VERSION 5.7 ;
  NOWIREEXTENSIONATPIN ON ;
  DIVIDERCHAR "/" ;
  BUSBITCHARS "[]" ;
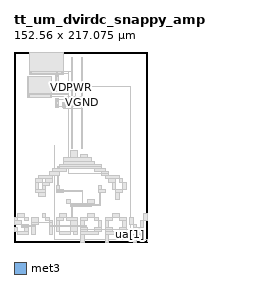
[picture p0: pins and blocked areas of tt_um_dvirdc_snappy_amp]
MACRO tt_um_dvirdc_snappy_amp
  CLASS BLOCK ;
  FOREIGN tt_um_dvirdc_snappy_amp ;
  ORIGIN 0.000 0.000 ;
  SIZE 152.560 BY 217.075 ;
  PIN VDPWR
    DIRECTION INOUT ;
    USE POWER ;
    PORT
      LAYER met3 ;
        RECT 65.995 175.995 66.005 176.005 ;
    END
  END VDPWR
  PIN VGND
    DIRECTION INOUT ;
    USE GROUND ;
    PORT
      LAYER met3 ;
        RECT 77.995 158.995 78.005 159.005 ;
    END
  END VGND
  PIN ua[0]
    DIRECTION INOUT ;
    USE ANALOG ;
    PORT
      LAYER met3 ;
        RECT 152.255 0.595 152.265 0.605 ;
    END
  END ua[0]
  PIN ua[1]
    DIRECTION INOUT ;
    USE ANALOG ;
    ANTENNADIFFAREA 2.320000 ;
    PORT
      LAYER met3 ;
        RECT 132.935 0.995 132.945 1.005 ;
    END
  END ua[1]
  OBS
      LAYER pwell ;
        RECT 17.735 191.735 56.715 217.075 ;
        RECT 15.735 164.735 43.375 189.075 ;
        RECT 47.735 171.735 50.805 191.655 ;
        RECT 47.735 153.735 50.805 163.955 ;
        RECT 55.735 153.735 58.985 159.835 ;
      LAYER li1 ;
        RECT 17.915 216.725 56.535 216.895 ;
        RECT 17.915 192.085 18.085 216.725 ;
        RECT 18.565 192.565 19.975 194.725 ;
        RECT 54.475 192.565 55.885 194.725 ;
        RECT 19.050 192.520 19.490 192.565 ;
        RECT 54.960 192.520 55.400 192.565 ;
        RECT 56.365 192.085 56.535 216.725 ;
        RECT 17.915 191.915 56.535 192.085 ;
        RECT 47.915 191.305 50.625 191.475 ;
        RECT 15.915 188.725 43.195 188.895 ;
        RECT 15.915 165.085 16.085 188.725 ;
        RECT 16.565 165.565 17.975 167.725 ;
        RECT 41.135 165.565 42.545 167.725 ;
        RECT 17.050 165.520 17.490 165.565 ;
        RECT 41.620 165.520 42.060 165.565 ;
        RECT 43.025 165.085 43.195 188.725 ;
        RECT 47.915 172.085 48.085 191.305 ;
        RECT 49.050 190.825 49.490 190.870 ;
        RECT 48.565 188.665 49.975 190.825 ;
        RECT 48.565 172.565 49.975 174.725 ;
        RECT 49.050 172.520 49.490 172.565 ;
        RECT 50.455 172.085 50.625 191.305 ;
        RECT 47.915 171.915 50.625 172.085 ;
        RECT 15.915 164.915 43.195 165.085 ;
        RECT 47.915 163.605 50.625 163.775 ;
        RECT 47.915 154.085 48.085 163.605 ;
        RECT 49.050 163.125 49.490 163.170 ;
        RECT 48.565 160.965 49.975 163.125 ;
        RECT 48.565 154.565 49.975 156.725 ;
        RECT 49.050 154.520 49.490 154.565 ;
        RECT 50.455 154.085 50.625 163.605 ;
        RECT 47.915 153.915 50.625 154.085 ;
        RECT 55.915 159.485 58.805 159.655 ;
        RECT 55.915 154.085 56.085 159.485 ;
        RECT 56.715 158.975 57.215 159.145 ;
        RECT 57.505 158.975 58.005 159.145 ;
        RECT 56.485 154.765 56.655 158.805 ;
        RECT 57.275 154.765 57.445 158.805 ;
        RECT 58.065 154.765 58.235 158.805 ;
        RECT 56.715 154.425 57.215 154.595 ;
        RECT 57.505 154.425 58.005 154.595 ;
        RECT 58.635 154.085 58.805 159.485 ;
        RECT 55.915 153.915 58.805 154.085 ;
      LAYER met1 ;
        RECT 18.615 192.595 19.925 194.700 ;
        RECT 54.525 192.595 55.835 194.700 ;
        RECT 19.020 192.490 19.520 192.595 ;
        RECT 54.930 192.490 55.430 192.595 ;
        RECT 49.020 190.795 49.520 190.900 ;
        RECT 48.615 188.690 49.925 190.795 ;
        RECT 48.615 172.595 49.925 174.700 ;
        RECT 49.020 172.490 49.520 172.595 ;
        RECT 16.615 165.595 17.925 167.700 ;
        RECT 41.185 165.595 42.495 167.700 ;
        RECT 17.020 165.490 17.520 165.595 ;
        RECT 41.590 165.490 42.090 165.595 ;
        RECT 49.020 163.095 49.520 163.200 ;
        RECT 48.615 160.990 49.925 163.095 ;
        RECT 59.250 159.290 59.750 159.390 ;
        RECT 56.820 159.175 59.750 159.290 ;
        RECT 56.735 158.990 59.750 159.175 ;
        RECT 56.735 158.945 57.195 158.990 ;
        RECT 57.525 158.945 57.985 158.990 ;
        RECT 59.250 158.890 59.750 158.990 ;
        RECT 56.455 157.030 56.685 158.785 ;
        RECT 57.245 157.030 57.475 158.785 ;
        RECT 58.035 157.030 58.265 158.785 ;
        RECT 48.615 154.595 49.925 156.700 ;
        RECT 56.320 156.530 56.820 157.030 ;
        RECT 57.110 156.530 57.610 157.030 ;
        RECT 57.900 156.530 58.400 157.030 ;
        RECT 56.455 154.785 56.685 156.530 ;
        RECT 57.245 154.785 57.475 156.530 ;
        RECT 58.035 154.785 58.265 156.530 ;
        RECT 49.020 154.490 49.520 154.595 ;
        RECT 56.735 154.395 57.195 154.625 ;
        RECT 57.525 154.395 57.985 154.625 ;
        RECT 57.110 153.750 57.610 154.250 ;
      LAYER met2 ;
        RECT 65.850 195.280 66.150 195.650 ;
        RECT 65.720 194.720 66.280 195.280 ;
        RECT 61.850 193.020 62.150 193.150 ;
        RECT 18.990 192.460 19.550 193.020 ;
        RECT 54.900 192.460 55.460 193.020 ;
        RECT 61.720 192.460 62.280 193.020 ;
        RECT 48.990 190.370 49.550 190.930 ;
        RECT 48.990 172.460 49.550 173.020 ;
        RECT 61.850 169.280 62.150 192.460 ;
        RECT 65.850 189.850 66.150 194.720 ;
        RECT 69.850 177.850 133.090 178.150 ;
        RECT 65.720 175.720 66.280 176.280 ;
        RECT 69.850 173.020 70.150 177.850 ;
        RECT 69.720 172.460 70.280 173.020 ;
        RECT 61.720 168.720 62.280 169.280 ;
        RECT 16.990 165.460 17.550 166.020 ;
        RECT 41.560 165.460 42.120 166.020 ;
        RECT 48.990 162.670 49.550 163.230 ;
        RECT 61.850 159.420 62.150 168.720 ;
        RECT 59.220 158.860 59.780 159.420 ;
        RECT 61.720 158.860 62.280 159.420 ;
        RECT 56.290 158.150 56.850 158.280 ;
        RECT 56.290 157.850 58.300 158.150 ;
        RECT 56.290 157.720 56.850 157.850 ;
        RECT 56.420 157.030 56.720 157.720 ;
        RECT 58.000 157.030 58.300 157.850 ;
        RECT 56.320 156.530 56.820 157.030 ;
        RECT 57.110 156.530 57.610 157.030 ;
        RECT 57.900 156.530 58.400 157.030 ;
        RECT 57.210 155.780 57.510 156.530 ;
        RECT 57.080 155.220 57.640 155.780 ;
        RECT 48.990 154.460 49.550 155.020 ;
        RECT 57.110 153.750 57.610 154.250 ;
        RECT 57.210 153.080 57.510 153.750 ;
        RECT 57.080 152.520 57.640 153.080 ;
        RECT 61.850 108.280 62.150 158.860 ;
        RECT 69.850 158.280 70.150 172.460 ;
        RECT 77.720 166.220 78.280 166.780 ;
        RECT 73.850 163.230 74.150 163.650 ;
        RECT 73.720 162.670 74.280 163.230 ;
        RECT 69.720 157.720 70.280 158.280 ;
        RECT 69.850 154.850 70.150 157.720 ;
        RECT 73.850 155.780 74.150 162.670 ;
        RECT 77.850 159.280 78.150 166.220 ;
        RECT 77.720 158.720 78.280 159.280 ;
        RECT 73.720 155.220 74.280 155.780 ;
        RECT 73.850 154.850 74.150 155.220 ;
        RECT 77.850 155.020 78.150 158.720 ;
        RECT 77.720 154.460 78.280 155.020 ;
        RECT 77.850 153.080 78.150 154.460 ;
        RECT 77.720 152.520 78.280 153.080 ;
        RECT 77.850 152.350 78.150 152.520 ;
        RECT 61.720 107.720 62.280 108.280 ;
        RECT 61.850 77.850 62.150 107.720 ;
        RECT 132.790 1.280 133.090 177.850 ;
        RECT 132.660 0.720 133.220 1.280 ;
      LAYER met3 ;
        RECT 65.720 195.160 66.280 195.280 ;
        RECT 19.110 194.840 66.280 195.160 ;
        RECT 19.110 193.020 19.430 194.840 ;
        RECT 18.990 192.460 19.550 193.020 ;
        RECT 49.110 190.930 49.430 194.840 ;
        RECT 65.720 194.720 66.280 194.840 ;
        RECT 54.900 192.900 55.460 193.020 ;
        RECT 61.720 192.900 62.280 193.020 ;
        RECT 54.900 192.580 62.280 192.900 ;
        RECT 54.900 192.460 55.460 192.580 ;
        RECT 61.720 192.460 62.280 192.580 ;
        RECT 48.990 190.370 49.550 190.930 ;
        RECT 65.700 175.700 66.300 176.300 ;
        RECT 48.990 172.900 49.550 173.020 ;
        RECT 69.720 172.900 70.280 173.020 ;
        RECT 48.990 172.580 70.280 172.900 ;
        RECT 48.990 172.460 49.550 172.580 ;
        RECT 69.720 172.460 70.280 172.580 ;
        RECT 61.720 169.160 62.280 169.280 ;
        RECT 17.110 168.840 62.280 169.160 ;
        RECT 17.110 166.020 17.430 168.840 ;
        RECT 61.720 168.720 62.280 168.840 ;
        RECT 77.720 166.660 78.280 166.780 ;
        RECT 41.680 166.340 78.280 166.660 ;
        RECT 41.680 166.020 42.000 166.340 ;
        RECT 77.720 166.220 78.280 166.340 ;
        RECT 16.990 165.460 17.550 166.020 ;
        RECT 41.560 165.460 42.120 166.020 ;
        RECT 48.990 163.110 49.550 163.230 ;
        RECT 73.720 163.110 74.280 163.230 ;
        RECT 48.990 162.790 74.280 163.110 ;
        RECT 48.990 162.670 49.550 162.790 ;
        RECT 73.720 162.670 74.280 162.790 ;
        RECT 59.220 159.300 59.780 159.420 ;
        RECT 61.720 159.300 62.280 159.420 ;
        RECT 59.220 158.980 62.280 159.300 ;
        RECT 59.220 158.860 59.780 158.980 ;
        RECT 61.720 158.860 62.280 158.980 ;
        RECT 77.700 158.700 78.300 159.300 ;
        RECT 56.290 158.160 56.850 158.280 ;
        RECT 69.720 158.160 70.280 158.280 ;
        RECT 56.290 157.840 70.280 158.160 ;
        RECT 56.290 157.720 56.850 157.840 ;
        RECT 69.720 157.720 70.280 157.840 ;
        RECT 57.080 155.660 57.640 155.780 ;
        RECT 73.720 155.660 74.280 155.780 ;
        RECT 57.080 155.340 74.280 155.660 ;
        RECT 57.080 155.220 57.640 155.340 ;
        RECT 73.720 155.220 74.280 155.340 ;
        RECT 48.990 154.900 49.550 155.020 ;
        RECT 77.720 154.900 78.280 155.020 ;
        RECT 48.990 154.580 78.280 154.900 ;
        RECT 48.990 154.460 49.550 154.580 ;
        RECT 77.720 154.460 78.280 154.580 ;
        RECT 57.080 152.960 57.640 153.080 ;
        RECT 77.720 152.960 78.280 153.080 ;
        RECT 57.080 152.640 78.280 152.960 ;
        RECT 57.080 152.520 57.640 152.640 ;
        RECT 77.720 152.520 78.280 152.640 ;
        RECT 46.000 84.400 46.400 110.200 ;
        RECT 61.700 107.700 62.300 108.300 ;
        RECT 64.000 96.400 72.400 104.400 ;
        RECT 76.000 96.400 84.400 100.400 ;
        RECT 56.000 92.400 88.400 96.400 ;
        RECT 56.000 88.400 92.400 92.400 ;
        RECT 52.000 86.450 100.400 88.400 ;
        RECT 49.950 85.950 100.400 86.450 ;
        RECT 49.950 84.400 50.450 85.950 ;
        RECT 52.000 84.400 100.400 85.950 ;
        RECT 44.000 84.000 104.400 84.400 ;
        RECT 44.000 80.400 60.400 84.000 ;
        RECT 40.000 80.000 60.400 80.400 ;
        RECT 92.000 80.400 104.400 84.000 ;
        RECT 92.000 80.000 108.400 80.400 ;
        RECT 40.000 76.400 52.400 80.000 ;
        RECT 28.000 76.000 52.400 76.400 ;
        RECT 100.000 76.400 108.400 80.000 ;
        RECT 100.000 76.000 120.400 76.400 ;
        RECT 28.000 72.400 44.400 76.000 ;
        RECT 24.000 72.000 44.400 72.400 ;
        RECT 24.000 68.400 32.400 72.000 ;
        RECT 36.000 68.400 44.400 72.000 ;
        RECT 24.000 68.000 44.400 68.400 ;
        RECT 24.000 60.400 28.400 68.000 ;
        RECT 32.000 64.000 40.400 68.000 ;
        RECT 32.000 60.400 36.400 64.000 ;
        RECT 24.000 56.000 36.400 60.400 ;
        RECT 28.000 52.000 36.400 56.000 ;
        RECT 4.000 28.400 12.400 32.400 ;
        RECT 32.000 28.400 36.400 32.400 ;
        RECT 0.000 28.000 16.400 28.400 ;
        RECT 0.000 24.400 4.400 28.000 ;
        RECT 0.000 20.400 8.400 24.400 ;
        RECT 12.000 24.000 16.400 28.000 ;
        RECT 20.000 22.450 28.400 28.400 ;
        RECT 32.000 28.000 40.400 28.400 ;
        RECT 36.000 24.400 40.400 28.000 ;
        RECT 36.000 24.000 44.400 24.400 ;
        RECT 40.000 22.450 44.400 24.000 ;
        RECT 20.000 21.950 44.400 22.450 ;
        RECT 0.000 20.000 16.400 20.400 ;
        RECT 8.000 18.450 16.400 20.000 ;
        RECT 20.000 20.000 28.400 21.950 ;
        RECT 20.000 18.450 24.400 20.000 ;
        RECT 8.000 17.950 24.400 18.450 ;
        RECT 0.000 12.400 4.400 16.400 ;
        RECT 8.000 16.000 16.400 17.950 ;
        RECT 12.000 12.400 16.400 16.000 ;
        RECT 0.000 12.000 16.400 12.400 ;
        RECT 4.000 8.000 16.400 12.000 ;
        RECT 20.000 8.000 24.400 17.950 ;
        RECT 40.000 18.450 44.400 21.950 ;
        RECT 46.000 18.450 46.400 76.000 ;
        RECT 49.950 64.400 50.450 76.000 ;
        RECT 104.000 72.400 120.400 76.000 ;
        RECT 104.000 72.000 124.400 72.400 ;
        RECT 108.000 68.000 116.400 72.000 ;
        RECT 120.000 68.400 124.400 72.000 ;
        RECT 120.000 68.000 128.400 68.400 ;
        RECT 48.000 60.400 52.400 64.400 ;
        RECT 96.000 60.400 100.400 64.400 ;
        RECT 112.000 60.400 116.400 68.000 ;
        RECT 124.000 60.400 128.400 68.000 ;
        RECT 48.000 58.450 56.400 60.400 ;
        RECT 48.000 57.950 78.450 58.450 ;
        RECT 48.000 56.000 56.400 57.950 ;
        RECT 60.000 44.400 64.400 48.400 ;
        RECT 77.950 44.400 78.450 57.950 ;
        RECT 96.000 56.000 104.400 60.400 ;
        RECT 112.000 60.000 128.400 60.400 ;
        RECT 116.000 56.000 124.400 60.000 ;
        RECT 84.000 44.400 92.400 48.400 ;
        RECT 60.000 44.000 92.400 44.400 ;
        RECT 64.000 42.450 88.400 44.000 ;
        RECT 97.950 42.450 98.450 56.000 ;
        RECT 116.000 48.000 120.400 56.000 ;
        RECT 64.000 41.950 98.450 42.450 ;
        RECT 64.000 40.000 88.400 41.950 ;
        RECT 52.000 28.400 60.400 32.400 ;
        RECT 65.950 28.400 66.450 40.000 ;
        RECT 84.000 28.400 92.400 32.400 ;
        RECT 112.000 28.400 120.400 32.400 ;
        RECT 48.000 28.000 72.400 28.400 ;
        RECT 48.000 24.000 56.400 28.000 ;
        RECT 60.000 24.000 72.400 28.000 ;
        RECT 48.000 18.450 52.400 24.000 ;
        RECT 64.000 18.450 72.400 24.000 ;
        RECT 76.000 28.000 96.400 28.400 ;
        RECT 76.000 24.000 84.400 28.000 ;
        RECT 92.000 24.400 96.400 28.000 ;
        RECT 104.000 28.000 128.400 28.400 ;
        RECT 92.000 24.000 100.400 24.400 ;
        RECT 76.000 18.450 80.400 24.000 ;
        RECT 40.000 17.950 82.450 18.450 ;
        RECT 40.000 8.000 44.400 17.950 ;
        RECT 46.000 3.200 46.400 17.950 ;
        RECT 48.000 12.400 52.400 17.950 ;
        RECT 64.000 12.400 72.400 17.950 ;
        RECT 48.000 12.000 72.400 12.400 ;
        RECT 52.000 8.000 64.400 12.000 ;
        RECT 68.000 8.000 72.400 12.000 ;
        RECT 76.000 16.400 80.400 17.950 ;
        RECT 81.950 16.400 82.450 17.950 ;
        RECT 96.000 16.400 100.400 24.000 ;
        RECT 76.000 14.450 84.400 16.400 ;
        RECT 92.000 14.450 100.400 16.400 ;
        RECT 104.000 24.000 112.400 28.000 ;
        RECT 120.000 24.000 128.400 28.000 ;
        RECT 104.000 16.400 108.400 24.000 ;
        RECT 124.000 16.400 128.400 24.000 ;
        RECT 132.000 20.400 136.400 28.400 ;
        RECT 148.000 24.400 152.400 32.400 ;
        RECT 144.000 24.000 152.400 24.400 ;
        RECT 132.000 20.000 140.400 20.400 ;
        RECT 104.000 14.450 112.400 16.400 ;
        RECT 120.000 14.450 128.400 16.400 ;
        RECT 136.000 16.400 140.400 20.000 ;
        RECT 144.000 16.400 148.400 24.000 ;
        RECT 136.000 16.000 148.400 16.400 ;
        RECT 136.000 14.450 144.400 16.000 ;
        RECT 76.000 13.950 144.400 14.450 ;
        RECT 76.000 12.400 84.400 13.950 ;
        RECT 92.000 12.400 100.400 13.950 ;
        RECT 76.000 12.000 100.400 12.400 ;
        RECT 104.000 12.400 112.400 13.950 ;
        RECT 120.000 12.400 128.400 13.950 ;
        RECT 104.000 12.000 128.400 12.400 ;
        RECT 136.000 12.000 144.400 13.950 ;
        RECT 76.000 8.000 96.400 12.000 ;
        RECT 104.000 8.000 124.400 12.000 ;
        RECT 140.000 8.400 144.400 12.000 ;
        RECT 76.000 3.200 80.400 8.000 ;
        RECT 104.000 3.200 108.400 8.000 ;
        RECT 136.000 4.000 144.400 8.400 ;
        RECT 136.000 3.200 140.400 4.000 ;
        RECT 46.000 2.800 152.460 3.200 ;
        RECT 76.000 0.000 80.400 2.800 ;
        RECT 104.000 0.000 108.400 2.800 ;
        RECT 132.640 0.700 133.240 1.300 ;
        RECT 136.000 0.000 140.400 2.800 ;
        RECT 152.060 0.900 152.460 2.800 ;
        RECT 151.960 0.605 152.560 0.900 ;
        RECT 151.960 0.595 152.255 0.605 ;
        RECT 152.265 0.595 152.560 0.605 ;
        RECT 151.960 0.300 152.560 0.595 ;
      LAYER met4 ;
        RECT 61.700 107.700 62.300 108.300 ;
        RECT 61.750 96.400 62.250 107.700 ;
        RECT 65.300 107.300 66.700 210.700 ;
        RECT 77.300 107.300 78.700 210.700 ;
        RECT 64.000 96.400 72.400 104.400 ;
        RECT 76.000 96.400 84.400 100.400 ;
        RECT 56.000 92.400 88.400 96.400 ;
        RECT 56.000 88.400 92.400 92.400 ;
        RECT 52.000 86.450 100.400 88.400 ;
        RECT 49.950 85.950 100.400 86.450 ;
        RECT 49.950 84.400 50.450 85.950 ;
        RECT 52.000 84.400 100.400 85.950 ;
        RECT 44.000 84.000 104.400 84.400 ;
        RECT 44.000 80.400 60.400 84.000 ;
        RECT 40.000 80.000 60.400 80.400 ;
        RECT 40.000 76.400 52.400 80.000 ;
        RECT 61.750 78.450 62.250 84.000 ;
        RECT 92.000 80.400 104.400 84.000 ;
        RECT 92.000 80.000 108.400 80.400 ;
        RECT 100.000 78.450 108.400 80.000 ;
        RECT 61.750 77.950 108.400 78.450 ;
        RECT 28.000 76.000 52.400 76.400 ;
        RECT 100.000 76.400 108.400 77.950 ;
        RECT 100.000 76.000 120.400 76.400 ;
        RECT 28.000 72.400 44.400 76.000 ;
        RECT 24.000 72.000 44.400 72.400 ;
        RECT 24.000 68.400 32.400 72.000 ;
        RECT 36.000 68.400 44.400 72.000 ;
        RECT 24.000 68.000 44.400 68.400 ;
        RECT 24.000 60.400 28.400 68.000 ;
        RECT 32.000 64.000 40.400 68.000 ;
        RECT 49.950 64.400 50.450 76.000 ;
        RECT 104.000 72.400 120.400 76.000 ;
        RECT 104.000 72.000 124.400 72.400 ;
        RECT 108.000 68.000 116.400 72.000 ;
        RECT 120.000 68.400 124.400 72.000 ;
        RECT 120.000 68.000 128.400 68.400 ;
        RECT 32.000 60.400 36.400 64.000 ;
        RECT 24.000 56.000 36.400 60.400 ;
        RECT 48.000 60.400 52.400 64.400 ;
        RECT 96.000 60.400 100.400 64.400 ;
        RECT 112.000 60.400 116.400 68.000 ;
        RECT 124.000 60.400 128.400 68.000 ;
        RECT 48.000 58.450 56.400 60.400 ;
        RECT 48.000 57.950 78.450 58.450 ;
        RECT 48.000 56.000 56.400 57.950 ;
        RECT 28.000 52.000 36.400 56.000 ;
        RECT 60.000 44.400 64.400 48.400 ;
        RECT 77.950 44.400 78.450 57.950 ;
        RECT 96.000 56.000 104.400 60.400 ;
        RECT 112.000 60.000 128.400 60.400 ;
        RECT 116.000 56.000 124.400 60.000 ;
        RECT 84.000 44.400 92.400 48.400 ;
        RECT 60.000 44.000 92.400 44.400 ;
        RECT 64.000 42.450 88.400 44.000 ;
        RECT 97.950 42.450 98.450 56.000 ;
        RECT 116.000 48.000 120.400 56.000 ;
        RECT 64.000 41.950 98.450 42.450 ;
        RECT 64.000 40.000 88.400 41.950 ;
        RECT 4.000 28.400 12.400 32.400 ;
        RECT 32.000 28.400 36.400 32.400 ;
        RECT 52.000 28.400 60.400 32.400 ;
        RECT 65.950 28.400 66.450 40.000 ;
        RECT 84.000 28.400 92.400 32.400 ;
        RECT 112.000 28.400 120.400 32.400 ;
        RECT 0.000 28.000 16.400 28.400 ;
        RECT 0.000 24.400 4.400 28.000 ;
        RECT 0.000 20.400 8.400 24.400 ;
        RECT 12.000 24.000 16.400 28.000 ;
        RECT 20.000 22.450 28.400 28.400 ;
        RECT 32.000 28.000 40.400 28.400 ;
        RECT 36.000 24.400 40.400 28.000 ;
        RECT 48.000 28.000 72.400 28.400 ;
        RECT 36.000 24.000 44.400 24.400 ;
        RECT 40.000 22.450 44.400 24.000 ;
        RECT 20.000 21.950 44.400 22.450 ;
        RECT 0.000 20.000 16.400 20.400 ;
        RECT 8.000 18.450 16.400 20.000 ;
        RECT 20.000 20.000 28.400 21.950 ;
        RECT 20.000 18.450 24.400 20.000 ;
        RECT 8.000 17.950 24.400 18.450 ;
        RECT 0.000 12.400 4.400 16.400 ;
        RECT 8.000 16.000 16.400 17.950 ;
        RECT 12.000 12.400 16.400 16.000 ;
        RECT 0.000 12.000 16.400 12.400 ;
        RECT 4.000 8.000 16.400 12.000 ;
        RECT 20.000 8.000 24.400 17.950 ;
        RECT 40.000 18.450 44.400 21.950 ;
        RECT 48.000 24.000 56.400 28.000 ;
        RECT 60.000 24.000 72.400 28.000 ;
        RECT 48.000 18.450 52.400 24.000 ;
        RECT 64.000 18.450 72.400 24.000 ;
        RECT 76.000 28.000 96.400 28.400 ;
        RECT 76.000 24.000 84.400 28.000 ;
        RECT 92.000 24.400 96.400 28.000 ;
        RECT 104.000 28.000 128.400 28.400 ;
        RECT 92.000 24.000 100.400 24.400 ;
        RECT 76.000 18.450 80.400 24.000 ;
        RECT 40.000 17.950 82.450 18.450 ;
        RECT 40.000 8.000 44.400 17.950 ;
        RECT 48.000 12.400 52.400 17.950 ;
        RECT 64.000 12.400 72.400 17.950 ;
        RECT 48.000 12.000 72.400 12.400 ;
        RECT 52.000 8.000 64.400 12.000 ;
        RECT 68.000 8.000 72.400 12.000 ;
        RECT 76.000 16.400 80.400 17.950 ;
        RECT 81.950 16.400 82.450 17.950 ;
        RECT 96.000 16.400 100.400 24.000 ;
        RECT 76.000 14.450 84.400 16.400 ;
        RECT 92.000 14.450 100.400 16.400 ;
        RECT 104.000 24.000 112.400 28.000 ;
        RECT 120.000 24.000 128.400 28.000 ;
        RECT 104.000 16.400 108.400 24.000 ;
        RECT 124.000 16.400 128.400 24.000 ;
        RECT 132.000 20.400 136.400 28.400 ;
        RECT 148.000 24.400 152.400 32.400 ;
        RECT 144.000 24.000 152.400 24.400 ;
        RECT 132.000 20.000 140.400 20.400 ;
        RECT 104.000 14.450 112.400 16.400 ;
        RECT 120.000 14.450 128.400 16.400 ;
        RECT 136.000 16.400 140.400 20.000 ;
        RECT 144.000 16.400 148.400 24.000 ;
        RECT 136.000 16.000 148.400 16.400 ;
        RECT 136.000 14.450 144.400 16.000 ;
        RECT 76.000 13.950 144.400 14.450 ;
        RECT 76.000 12.400 84.400 13.950 ;
        RECT 92.000 12.400 100.400 13.950 ;
        RECT 76.000 12.000 100.400 12.400 ;
        RECT 104.000 12.400 112.400 13.950 ;
        RECT 120.000 12.400 128.400 13.950 ;
        RECT 104.000 12.000 128.400 12.400 ;
        RECT 136.000 12.000 144.400 13.950 ;
        RECT 76.000 8.000 96.400 12.000 ;
        RECT 104.000 8.000 124.400 12.000 ;
        RECT 140.000 8.400 144.400 12.000 ;
        RECT 76.000 0.000 80.400 8.000 ;
        RECT 104.000 0.000 108.400 8.000 ;
        RECT 136.000 4.000 144.400 8.400 ;
        RECT 132.640 0.700 133.240 1.300 ;
        RECT 136.000 0.000 140.400 4.000 ;
        RECT 151.960 0.300 152.560 0.900 ;
  END
END tt_um_dvirdc_snappy_amp
END LIBRARY

